One B-rep face of a CAD part: STEP entity #37.
In plain terms, the planar face has unit normal (1, 0, 0).
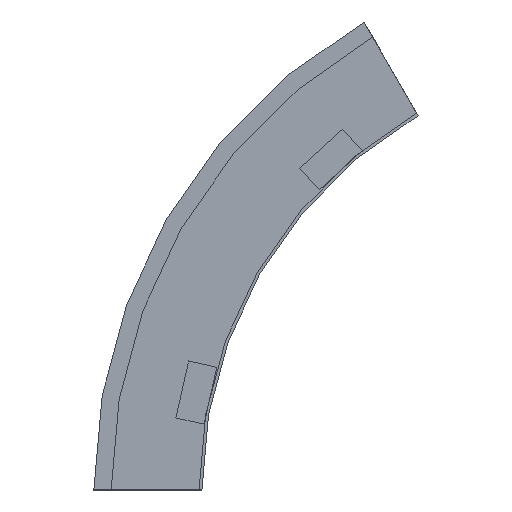
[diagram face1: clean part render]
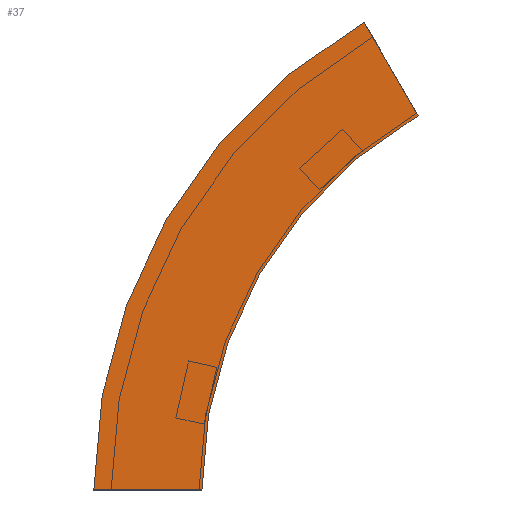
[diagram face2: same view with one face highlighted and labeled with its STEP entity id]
Its self-contained STEP definition (entity closure, numbers rounded to 3 decimals):
#16 = VERTEX_POINT ( 'NONE', #506 ) ;
#17 = PLANE ( 'NONE',  #358 ) ;
#20 = EDGE_CURVE ( 'NONE', #294, #16, #27, .T. ) ;
#21 = VECTOR ( 'NONE', #243, 1000. ) ;
#25 = DIRECTION ( 'NONE',  ( 0., 1., 0. ) ) ;
#27 = CIRCLE ( 'NONE', #314, 300. ) ;
#37 = ADVANCED_FACE ( 'NONE', ( #164 ), #17, .T. ) ;
#40 = VERTEX_POINT ( 'NONE', #332 ) ;
#66 = CARTESIAN_POINT ( 'NONE',  ( 0., -300., 0. ) ) ;
#70 = CARTESIAN_POINT ( 'NONE',  ( 0., 0., 0. ) ) ;
#85 = CARTESIAN_POINT ( 'NONE',  ( 0., -300., 0. ) ) ;
#103 = LINE ( 'NONE', #565, #227 ) ;
#124 = CARTESIAN_POINT ( 'NONE',  ( 0., 75., 0. ) ) ;
#130 = EDGE_CURVE ( 'NONE', #339, #40, #483, .T. ) ;
#164 = FACE_OUTER_BOUND ( 'NONE', #368, .T. ) ;
#201 = ORIENTED_EDGE ( 'NONE', *, *, #130, .T. ) ;
#227 = VECTOR ( 'NONE', #284, 1000. ) ;
#243 = DIRECTION ( 'NONE',  ( 0., 1., 0. ) ) ;
#247 = CARTESIAN_POINT ( 'NONE',  ( 0., 0., 0. ) ) ;
#248 = DIRECTION ( 'NONE',  ( 1., 0., 0. ) ) ;
#253 = DIRECTION ( 'NONE',  ( 0., 0., -1. ) ) ;
#263 = EDGE_CURVE ( 'NONE', #16, #40, #103, .T. ) ;
#284 = DIRECTION ( 'NONE',  ( 0., 0.5, 0.866 ) ) ;
#294 = VERTEX_POINT ( 'NONE', #393 ) ;
#306 = DIRECTION ( 'NONE',  ( 1., 0., 0. ) ) ;
#314 = AXIS2_PLACEMENT_3D ( 'NONE', #66, #248, #420 ) ;
#315 = AXIS2_PLACEMENT_3D ( 'NONE', #85, #306, #25 ) ;
#332 = CARTESIAN_POINT ( 'NONE',  ( 0., -112.5, 324.76 ) ) ;
#339 = VERTEX_POINT ( 'NONE', #124 ) ;
#348 = ORIENTED_EDGE ( 'NONE', *, *, #391, .T. ) ;
#358 = AXIS2_PLACEMENT_3D ( 'NONE', #70, #535, #253 ) ;
#368 = EDGE_LOOP ( 'NONE', ( #201, #537, #571, #348 ) ) ;
#391 = EDGE_CURVE ( 'NONE', #294, #339, #528, .T. ) ;
#393 = CARTESIAN_POINT ( 'NONE',  ( 0., 0., 0. ) ) ;
#420 = DIRECTION ( 'NONE',  ( 0., 1., 0. ) ) ;
#483 = CIRCLE ( 'NONE', #315, 375. ) ;
#506 = CARTESIAN_POINT ( 'NONE',  ( 0., -150., 259.808 ) ) ;
#528 = LINE ( 'NONE', #247, #21 ) ;
#535 = DIRECTION ( 'NONE',  ( 1., 0., 0. ) ) ;
#537 = ORIENTED_EDGE ( 'NONE', *, *, #263, .F. ) ;
#565 = CARTESIAN_POINT ( 'NONE',  ( 0., -150., 259.808 ) ) ;
#571 = ORIENTED_EDGE ( 'NONE', *, *, #20, .F. ) ;
